VERSION 5.7 ;
BUSBITCHARS "[]" ;
DIVIDERCHAR "/" ;

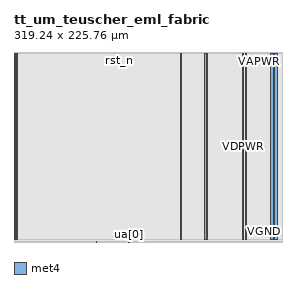
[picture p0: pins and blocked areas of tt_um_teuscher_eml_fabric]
MACRO tt_um_teuscher_eml_fabric
  CLASS BLOCK ;
  ORIGIN 0 0 ;
  FOREIGN tt_um_teuscher_eml_fabric 0 0 ;
  SIZE 319.240 BY 225.760 ;
  PIN rst_n
    DIRECTION INPUT ;
    USE SIGNAL ;
    PORT
      LAYER met4 ;
        RECT 125.430 224.760 125.730 225.760 ;
    END
  END rst_n
  PIN ua[0]
    DIRECTION INOUT ;
    USE SIGNAL ;
    PORT
      LAYER met4 ;
        RECT 136.170 0.000 137.070 1.000 ;
    END
  END ua[0]
  PIN ua[2]
    DIRECTION INOUT ;
    USE SIGNAL ;
    PORT
      LAYER met4 ;
        RECT 97.530 0.000 98.430 1.000 ;
    END
  END ua[2]
  PIN ui_in[0]
    DIRECTION INPUT ;
    USE SIGNAL ;
    PORT
      LAYER met4 ;
        RECT 122.670 224.760 122.970 225.760 ;
    END
  END ui_in[0]
  PIN ui_in[2]
    DIRECTION INPUT ;
    USE SIGNAL ;
    PORT
      LAYER met4 ;
        RECT 117.150 224.760 117.450 225.760 ;
    END
  END ui_in[2]
  PIN uo_out[0]
    DIRECTION OUTPUT ;
    USE SIGNAL ;
    PORT
      LAYER met4 ;
        RECT 78.510 224.760 78.810 225.760 ;
    END
  END uo_out[0]
  PIN VGND
    DIRECTION INOUT ;
    USE GROUND ;
    PORT
      LAYER met4 ;
        RECT 0.600 3.000 1.800 223.800 ;
        RECT 228.800 3.000 230.000 223.800 ;
        RECT 304.400 3.000 308.400 223.800 ;
    END
  END VGND
  PIN VAPWR
    DIRECTION INOUT ;
    USE POWER ;
    PORT
      LAYER met4 ;
        RECT 2.600 3.000 3.800 223.800 ;
        RECT 198.100 3.000 199.300 223.800 ;
        RECT 226.800 3.000 228.250 223.800 ;
        RECT 275.200 3.000 276.400 223.800 ;
        RECT 309.000 3.000 313.000 223.800 ;
    END
  END VAPWR
  PIN VDPWR
    DIRECTION INOUT ;
    USE POWER ;
    PORT
      LAYER met4 ;
        RECT 271.900 3.000 273.100 223.800 ;
    END
  END VDPWR
  OBS
    LAYER met1 ;
      RECT 0.000 0.000 319.240 225.760 ;
    LAYER met2 ;
      RECT 0.000 0.000 319.240 225.760 ;
    LAYER met3 ;
      RECT 0.000 0.000 319.240 225.760 ;
    LAYER met4 ;
      RECT 0.000 0.000 97.530 1.000 ;
      RECT 98.430 0.000 136.170 1.000 ;
      RECT 137.070 0.000 319.240 1.000 ;
      RECT 0.000 1.000 319.240 3.000 ;
      RECT 0.000 3.000 0.600 223.800 ;
      RECT 1.800 3.000 2.600 223.800 ;
      RECT 3.800 3.000 198.100 223.800 ;
      RECT 199.300 3.000 226.800 223.800 ;
      RECT 228.250 3.000 228.800 223.800 ;
      RECT 230.000 3.000 271.900 223.800 ;
      RECT 273.100 3.000 275.200 223.800 ;
      RECT 276.400 3.000 304.400 223.800 ;
      RECT 308.400 3.000 309.000 223.800 ;
      RECT 313.000 3.000 319.240 223.800 ;
      RECT 0.000 223.800 319.240 224.760 ;
      RECT 0.000 224.760 78.510 225.760 ;
      RECT 78.810 224.760 117.150 225.760 ;
      RECT 117.450 224.760 122.670 225.760 ;
      RECT 122.970 224.760 125.430 225.760 ;
      RECT 125.730 224.760 319.240 225.760 ;
  END
END tt_um_teuscher_eml_fabric

END LIBRARY
